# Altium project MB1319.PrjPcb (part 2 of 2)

## Sheet ST_LINK_V2-1.SchDoc: ST-LINK/V2-1
size A3; Date: Not used; ApprovedBy: Not used; CheckedBy: Not used; Author: Not used; CompanyName: STMicroelectronics; DrawnBy: Not used; Engineer: Not used; Organization: Not used; Address1: Not used; Address2: Not used; Address3: Not used; Address4: Not used; DocumentNumber: 8; Revision: Not used; SheetNumber: 8; SheetTotal: 8

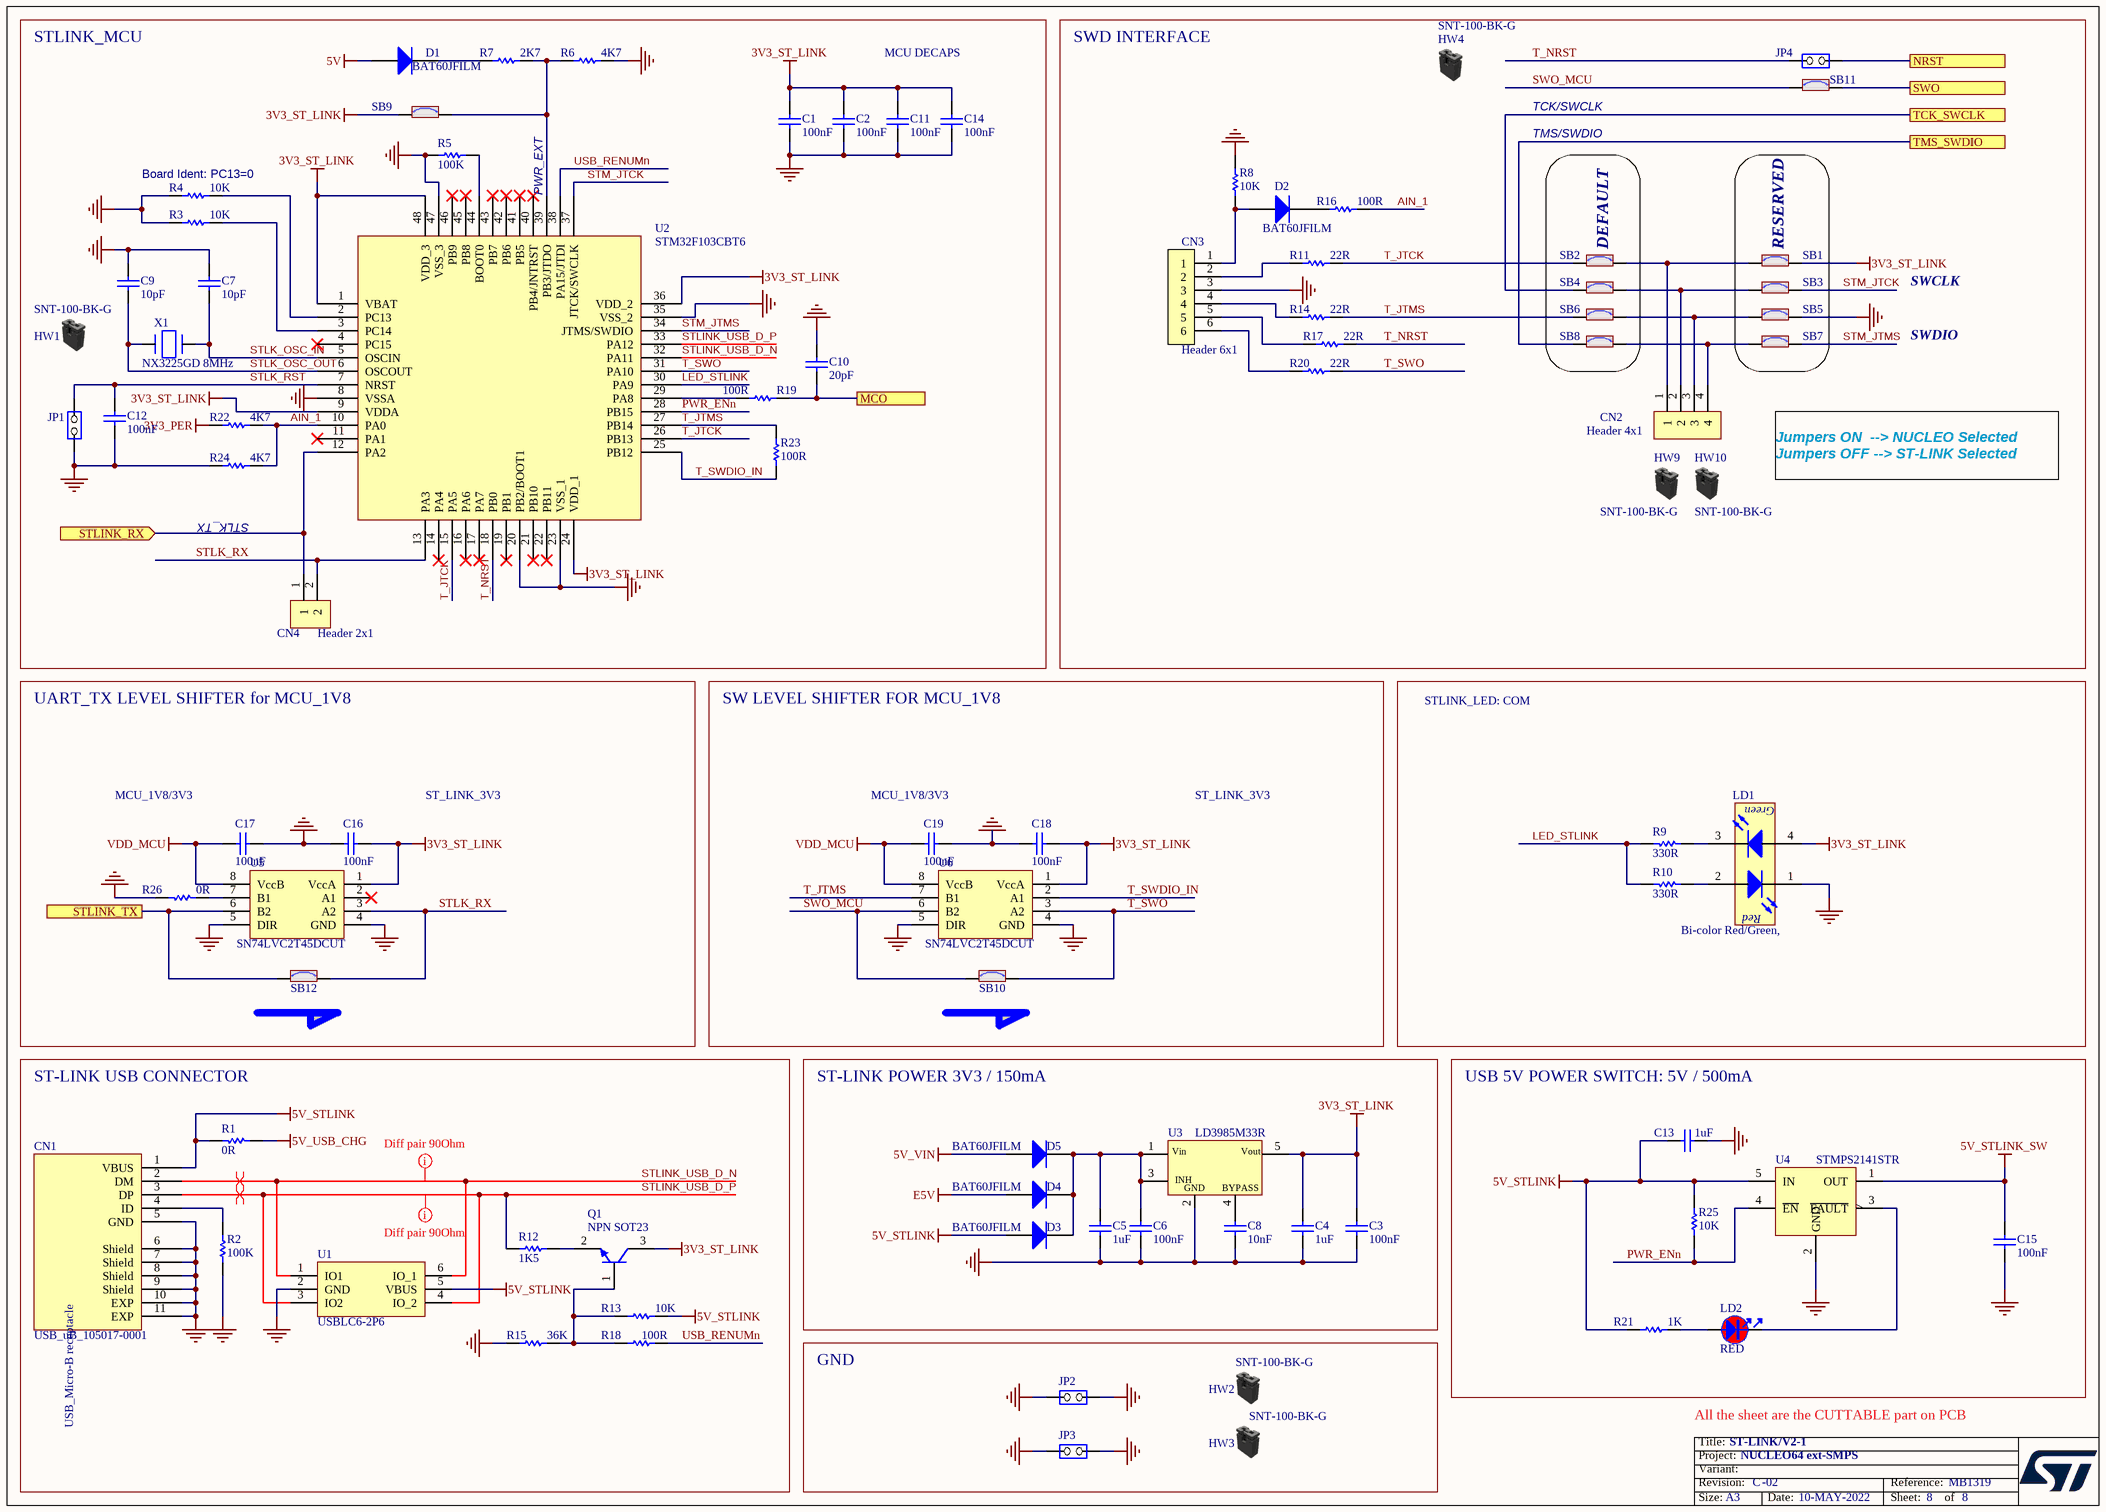
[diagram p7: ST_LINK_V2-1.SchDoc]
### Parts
C1  value 100nF  [C0603]  (hidden comment: Capacitor)
C2  value 100nF  [C0603]  (hidden comment: Capacitor)
C3  value 100nF  [C0603]  (hidden comment: Capacitor)
C4  value 1uF  [C0603]  (hidden comment: Capacitor)
C5  value 1uF  [C0603]  (hidden comment: Capacitor)
C6  value 100nF  [C0603]  (hidden comment: Capacitor)
C7  value 10pF  [C0402]  (hidden comment: Capacitor)
C8  value 10nF  [C0603]  (hidden comment: Capacitor)
C9  value 10pF  [C0402]  (hidden comment: Capacitor)
C10  value 20pF  [C0603]  (hidden comment: Capacitor)
C11  value 100nF  [C0603]  (hidden comment: Capacitor)
C12  value 100nF  [C0603]  (hidden comment: Capacitor)
C13  value 1uF  [C0603]  (hidden comment: Capacitor)
C14  value 100nF  [C0603]  (hidden comment: Capacitor)
C15  value 100nF  [C0603]  (hidden comment: Capacitor)
C16  value 100nF  [C0603]  (hidden comment: Capacitor)
C17  value 100nF  [C0603]  (hidden comment: Capacitor)
C18  value 100nF  [C0603]  (hidden comment: Capacitor)
C19  value 100nF  [C0603]  (hidden comment: Capacitor)
CN1  value USB_uB_105017-0001  [CON_USBMICROB_MOLEX_105017-0001_H2P90]  (hidden comment: USB_uB_105017.0001)
CN2  Header 4x1  [CON_SAMTEC_TSW-104-07-G-S]
CN3  Header 6x1  [CON_SAMTEC_TSW-106-07-X-S]
CN4  Header 2x1  [CON_SAMTEC_TSW-102-07-G-S]
D1  BAT60JFILM  [DIO_SOD323]
D2  BAT60JFILM  [DIO_SOD323]
D3  BAT60JFILM  [DIO_SOD323]
D4  BAT60JFILM  [DIO_SOD323]
D5  BAT60JFILM  [DIO_SOD323]
HW1  value SNT-100-BK-G  (hidden comment: Shunt Black 2.54mm)  (mechanical)
HW2  value SNT-100-BK-G  (hidden comment: Shunt Black 2.54mm)  (mechanical)
HW3  value SNT-100-BK-G  (hidden comment: Shunt Black 2.54mm)  (mechanical)
HW4  value SNT-100-BK-G  (hidden comment: Shunt Black 2.54mm)  (mechanical)
HW9  value SNT-100-BK-G  (hidden comment: Shunt Black 2.54mm)  (mechanical)
HW10  value SNT-100-BK-G  (hidden comment: Shunt Black 2.54mm)  (mechanical)
JP1  Jumper_Header 2x1  [CON_SAMTEC_TSW-102-07-G-S]  (value not drawn)
JP2  Jumper_Header 2x1  [CON_SAMTEC_TSW-102-09-X-S]  (value not drawn)
JP3  Jumper_Header 2x1  [CON_SAMTEC_TSW-102-09-X-S]  (value not drawn)
JP4  Jumper_Header 2x1  [CON_SAMTEC_TSW-102-07-G-S]  (value not drawn)
LD1  value Bi-color Red/Green,  [LED_BI-GR_HSMF-A201-A00J1]  (hidden comment: LD_BICOLOR_CMS)
LD2  value RED  [LED_0603_RED]  (hidden comment: LED_red)
Q1  value NPN SOT23  [NPN_SOT23]  (hidden comment: 9013-SOT23)
R1  value 0R  [R0603]  (hidden comment: Resistor)
R2  value 100K  [R0603]  (hidden comment: Resistor)
R3  value 10K  [R0603]  (hidden comment: Resistor)
R4  value 10K  [R0603]  (hidden comment: Resistor)
R5  value 100K  [R0603]  (hidden comment: Resistor)
R6  value 4K7  [R0603]  (hidden comment: Resistor)
R7  value 2K7  [R0603]  (hidden comment: Resistor)
R8  value 10K  [R0603]  (hidden comment: Resistor)
R9  value 330R  [R0603]  (hidden comment: Resistor)
R10  value 330R  [R0603]  (hidden comment: Resistor)
R11  value 22R  [R0603]  (hidden comment: Resistor)
R12  value 1K5  [R0603]  (hidden comment: Resistor)
R13  value 10K  [R0603]  (hidden comment: Resistor)
R14  value 22R  [R0603]  (hidden comment: Resistor)
R15  value 36K  [R0603]  (hidden comment: Resistor)
R16  value 100R  [R0603]  (hidden comment: Resistor)
R17  value 22R  [R0603]  (hidden comment: Resistor)
R18  value 100R  [R0603]  (hidden comment: Resistor)
R19  value 100R  [R0603]  (hidden comment: Resistor)
R20  value 22R  [R0603]  (hidden comment: Resistor)
R21  value 1K  [R0603]  (hidden comment: Resistor)
R22  value 4K7  [R0603]  (hidden comment: Resistor)
R23  value 100R  [R0603]  (hidden comment: Resistor)
R24  value 4K7  [R0603]  (hidden comment: Resistor)
R25  value 10K  [R0603]  (hidden comment: Resistor)
R26  value 0R  [R0603]  (hidden comment: Resistor)
SB1  SB_ON  [SOLDER-BRIDGE_R0603-0R]  (value not drawn)
SB2  SB_ON  [SOLDER-BRIDGE_R0603-0R]  (value not drawn)
SB3  SB_ON  [SOLDER-BRIDGE_R0603-0R]  (value not drawn)
SB4  SB_ON  [SOLDER-BRIDGE_R0603-0R]  (value not drawn)
SB5  SB_ON  [SOLDER-BRIDGE_R0603-0R]  (value not drawn)
SB6  SB_ON  [SOLDER-BRIDGE_R0603-0R]  (value not drawn)
SB7  SB_ON  [SOLDER-BRIDGE_R0603-0R]  (value not drawn)
SB8  SB_ON  [SOLDER-BRIDGE_R0603-0R]  (value not drawn)
SB9  SB_ON  [SOLDER-BRIDGE_R0603-0R]  (value not drawn)
SB10  SB_ON  [SOLDER-BRIDGE_R0603-0R]  (value not drawn)
SB11  SB_ON  [SOLDER-BRIDGE_R0603-0R]  (value not drawn)
SB12  SB_ON  [SOLDER-BRIDGE_R0603-0R]  (value not drawn)
U1  USBLC6-2P6  [ESD_SOT666]
U2  STM32F103CBT6  [ICC_LQFP48_7X7_P050]
U3  LD3985M33R  [REG_SOT23-5L]
U4  STMPS2141STR  [MOS_SOT23-5L]
U5  SN74LVC2T45DCUT  [ICC_VSSOP8_DCU_R-PDSO-G8_2X2P30_P050]
U6  SN74LVC2T45DCUT  [ICC_VSSOP8_DCU_R-PDSO-G8_2X2P30_P050]
X1  value NX3225GD 8MHz  [CRY_NX3225GD_2P]  (hidden comment: XTAL_2_PINS)

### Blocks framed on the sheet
STLINK_MCU: C1 C2 C7 C9-C12 C14 CN4 D1 HW1 JP1 R3-R7 R19 R22-R24 SB9 U2 X1
SWD INTERFACE: CN2 CN3 D2 HW4 HW9 HW10 JP4 R8 R11 R14 R16 R17 R20 SB11
DEFAULT: SB2 SB4 SB6 SB8
RESERVED: SB1 SB3 SB5 SB7
UART_TX LEVEL SHIFTER for MCU_1V8: C16 C17 R26 SB12 U5
SW LEVEL SHIFTER FOR MCU_1V8: C18 C19 SB10 U6
STLINK_LED: COM: LD1 R9 R10
ST-LINK USB CONNECTOR: CN1 Q1 R1 R2 R12 R13 R15 R18 U1
ST-LINK POWER 3V3 / 150mA: C3-C6 C8 D3-D5 U3
USB 5V POWER SWITCH: 5V / 500mA: C13 C15 LD2 R21 R25 U4
GND: HW2 HW3 JP2 JP3

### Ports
MCO, NRST, STLINK_RX (in), STLINK_TX, SWO, TCK_SWCLK, TMS_SWDIO

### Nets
3V3_PER: R22.1
3V3_ST_LINK: C1.2 C2.2 C3.2 C4.2 C11.2 C14.2 C16.1 C18.1 LD1.4(YellowGreen_anode) Q1.3(C) SB1.2 SB9.1 U2.1(VBAT) U2.9(VDDA) U2.24(VDD_1) U2.36(VDD_2) U2.48(VDD_3) U3.5(Vout) U5.1(VccA) U6.1(VccA)
5V: D1.1(A)
5V_STLINK: C13.1 CN1.1(VBUS) D3.1(A) R1.1 R13.1 R21.2 R25.1 U1.5(VBUS) U4.5(IN)
5V_STLINK_SW: C15.2 U4.1(OUT)
5V_USB_CHG: R1.2
5V_VIN: D5.1(A)
E5V: D4.1(A)
GND: C1.1 C2.1 C3.1 C4.1 C5.1 C6.1 C7.2 C8.1 C9.2 C10.2 C11.1 C12.1 C13.2 C14.1 C15.1 C16.2 C17.1 C18.2 C19.1 CN1.5(GND) CN1.6(Shield) CN1.7(Shield) CN1.8(Shield) CN1.9(Shield) CN1.10(EXP) CN1.11(EXP) CN3.3 JP1.1(COMMON) JP2.1(COMMON) JP2.2(NO) JP3.1(COMMON) JP3.2(NO) LD1.1(RED_cathode) R2.1 R3.1 R4.1 R5.1 R6.2 R8.2 R15.1 R24.1 R26.2 SB5.2 U1.2(GND) U2.8(VSSA) U2.20(PB2/BOOT1) U2.23(VSS_1) U2.35(VSS_2) U2.47(VSS_3) U3.2(GND) U4.2(GND) U5.4(GND) U5.5(DIR) U6.4(GND) U6.5(DIR)
VDD_MCU: C17.2 C19.2 U5.8(VccB) U6.8(VccB)
AIN_1: R16.2 R22.2 R24.2 U2.10(PA0)
LED_STLINK: R9.2 R10.2 U2.30(PA9)
MCO: C10.1 R19.2 ; port MCO
NRST: JP4.1(COMMON) ; port NRST
PA13: SB8.1 ; port TMS_SWDIO
PA14: SB4.1 ; port TCK_SWCLK
PB3: SB11.2 ; port SWO
PWR_ENn: R25.2 U2.28(PB15) U4.4(~{EN})
STLINK_RX: CN4.1 U2.12(PA2) ; port STLINK_RX
STLINK_TX: SB12.2 U5.6(B2) ; port STLINK_TX
STLINK_USB_D_N: CN1.2(DM) U1.1(IO1) U1.6(IO_1) U2.32(PA11)
STLINK_USB_D_P: CN1.3(DP) R12.2 U1.3(IO2) U1.4(IO_2) U2.33(PA12)
STLK_OSC_IN: C7.1 U2.5(OSCIN) X1.2(X2)
STLK_OSC_OUT: C9.1 U2.6(OSCOUT) X1.1(X1)
STLK_RST: C12.2 JP1.2(NO) U2.7(NRST)
STLK_RX: CN4.2 SB12.1 U2.13(PA3) U5.3(A2)
STM_JTCK: SB3.2 U2.37(JTCK/SWCLK)
STM_JTMS: SB7.2 U2.34(JTMS/SWDIO)
SWO_MCU: SB10.2 SB11.1 U6.6(B2)
T_JTCK: R11.2 SB2.1 U2.15(PA5) U2.26(PB13)
T_JTMS: R14.2 R23.2 SB6.1 U2.27(PB14) U6.7(B1)
T_NRST: JP4.2(NO) R17.2 U2.18(PB0)
T_SWDIO_IN: R23.1 U2.25(PB12) U6.2(A1)
T_SWO: R20.2 SB10.1 U2.31(PA10) U6.3(A2)
USB_RENUMn: R18.2 U2.38(PA15/JTDI)
NetC5_2: C5.2 C6.2 D3.2(K) D4.2(K) D5.2(K) U3.1(Vin) U3.3(CE)
NetC8_2: C8.2 U3.4(BYPASS)
NetCN1_4: CN1.4(ID) R2.2
NetCN2_1: CN2.1 SB1.1 SB2.2
NetCN2_2: CN2.2 SB3.1 SB4.2
NetCN2_3: CN2.3 SB5.1 SB6.2
NetCN2_4: CN2.4 SB7.1 SB8.2
NetCN3_1: CN3.1 D2.1(A) R8.1
NetCN3_2: CN3.2 R11.1
NetCN3_4: CN3.4 R14.1
NetCN3_5: CN3.5 R17.1
NetCN3_6: CN3.6 R20.1
NetD1_2: D1.2(K) R7.1
NetD2_2: D2.2(K) R16.1
NetLD1_2: LD1.2(Red_anode) R10.1
NetLD1_3: LD1.3(YellowGreen_cathode) R9.1
NetLD2_1: LD2.1 R21.1
NetLD2_2: LD2.2 U4.3(~{FAULT})
NetQ1_1: Q1.1(B) R13.2 R15.2 R18.1
NetQ1_2: Q1.2(E) R12.1
NetR3_2: R3.2 U2.3(PC14)
NetR4_2: R4.2 U2.2(PC13)
NetR5_2: R5.2 U2.44(BOOT0)
NetR6_1: R6.1 R7.2 SB9.2 U2.39(PB3/JTDO)
NetR19_1: R19.1 U2.29(PA8)
NetR26_1: R26.1 U5.7(B1)

Not connected (* = marked no-connect by the designer): U2 4(PC15)* 11(PA1)* 14(PA4)* 16(PA6)* 17(PA7)* 19(PB1)* 21(PB10)* 22(PB11)* 40(PB4/JNTRST)* 41(PB5)* 42(PB6)* 43(PB7)* 45(PB8)* 46(PB9)*; U5 2(A1)*

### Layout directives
mark named Diff pair 90Ohm: STLINK_USB_D_N, STLINK_USB_D_P
differential pair: STLINK_USB_D_N, STLINK_USB_D_P

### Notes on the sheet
- MCU DECAPS
- TCK/SWCLK
- (near R4) Board Ident: PC13=0
- TMS/SWDIO
- (near U2) PWR_EXT
- SWCLK
- SWDIO
- STLK_TX
- Jumpers ON  --> NUCLEO Selected
  Jumpers OFF --> ST-LINK Selected
- MCU_1V8/3V3
- ST_LINK_3V3
- All the sheet are the CUTTABLE part on PCB

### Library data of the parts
C1-C3 C11 C12 C14-C19 = MCD-00237: Capacitor, MLCC, 100nF, 6V3, X5R, +/-10%, 0603, T=0.8mm; Part_Preference: Not recommended; Manufacturer: YAGEO; Manufacturer_Part_Number: CC0603KRX5R5BB104; Component_Country_Of_Origin: China; ShowFields: YES; ID: 2631
C4 C13 = MCD-00238: Capacitor, MLCC, 1uF, 6V3, X5R, +/-10%, 0603, T=0,8mm; Manufacturer_Part_Number: CC0603KRX5R5BB105; Manufacturer: YAGEO; Part_Preference: Recommended
C5 = MCD-00010: Capacitor, MLCC, 1uF, 16V, X5R, +/-10%, 0603, T=0,8mm; Manufacturer_Part_Number: CC0603KRX5R7BB105; Manufacturer: YAGEO; Part_Preference: Recommended
C6 = MCD-00211: Capacitor, MLCC, 100nF, 16V, X7R, +/-10%, 0603, T=0,8mm; Manufacturer_Part_Number: CC0603KRX7R7BB104; Manufacturer: YAGEO; Part_Preference: Recommended; Order_Code_RS: 669-8763
C7 C9 = MCD-00015: Capacitor, MLCC, 10pF, 50V, NPO, +/-5%, 0402, T=0,5mm; Manufacturer_Part_Number: CC0402JRNPO9BN100; Manufacturer: YAGEO; Part_Preference: Recommended
C8 = MCD-00017: Capacitor, MLCC, 10nF, 50V, X7R, +/-10%, 0603, T=0.8mm; Manufacturer_Part_Number: CC0603KRX7R9BB103; Manufacturer: YAGEO; Part_Preference: Recommended; Order_Code_RS: 616-9537
C10 = MCD-00638: Capacitor, MLCC, 20pF, 50V, NPO, +/-5%, 0603, T=0,8mm; Manufacturer_Part_Number: CC0603JRNPO9BN200; Manufacturer: YAGEO; Part_Preference: Recommended
CN1 = MCD-00028: USB-MICRO-B, 0.65mm, RA, SMT, Bottom Mount,; Manufacturer_Part_Number: 1050170001; Manufacturer: MOLEX; Part_Type: Connector; Part_Preference: Recommended
CN2 = MCD-00029: Header, 4x1, 2,54mm, VR, TH, Height 5.84mm/2.54mm; Part_Type: Connector; Manufacturer_Part_Number: TSW-104-07-G-S; Manufacturer: SAMTEC; Part_Preference: Recommended
CN3 = MCD-00212: Header, 6x1, 2,54mm, VR, TH, Height 5.84mm/2.54mm; Manufacturer_Part_Number: TSW-106-07-G-S; Manufacturer: SAMTEC; Part_Type: Connector; Part_Preference: Recommended
CN4 = MCD-00032: Header, 2x1, 2,54mm, VR, TH, Height 5.84mm/2.54mm; Manufacturer_Part_Number: TSW-102-07-G-S; Manufacturer: SAMTEC; Part_Type: Connector; Part_Preference: Recommended; Alternate_Manufacturer: JIUBABA; Alternate_Manufacturer_Part_Number: 313102S111116
D1-D5 = MCD-00034: Manufacturer: STMICROELECTRONICS; Part_Type: Diode; BMS_Part_Number: 9151097; Part_Preference: Recommended; Manufacturer_HQ_COO: EU
HW1-HW4 HW9 HW10 = MCD-00043: SHUNT 2.54mm BLACK; Manufacturer: SAMTEC; Part_Type: Misc; Part_Preference: Recommended; Alternate_Manufacturer: JIUBABA; Alternate_Manufacturer_Part_Number: 316102S111A
JP1 JP4 = MCD-00045: Header, 2x1, 2,54mm, VR, TH, Height 5.84mm/2.54mm; Manufacturer_Part_Number: TSW-102-07-G-S; Manufacturer: SAMTEC; Part_Type: Connector; Part_Preference: Recommended; Alternate_Manufacturer: JIUBABA; LIANYI; Alternate_Manufacturer_Part_Number: 313102S111116;313102S111116; Value: Shunt not fitted
JP2 JP3 = MCD-00214: Header, 2x1, 2,54mm, VR, TH, Height 5.84mm/10.16mm; Manufacturer_Part_Number: TSW-102-09-G-S; Manufacturer: SAMTEC; Part_Type: Connector; Part_Preference: Recommended; Value: Header 2x1 16mm
LD1 = MCD-02360: Led, Bi-color Red/Green, 2V4, 30mA, 4-PLCC; Manufacturer_Part_Number: 67-22VRVGC/TR8; Manufacturer: EVERLIGHT; Part_Type: Display; Part_Preference: Recommended
LD2 = MCD-02899: LED, Red, VF : Min=1.75V , Max=2.35V, 25mA, 0603; Part_Type: Display; Part_Preference: Recommended; Manufacturer: EVERLIGHT; Manufacturer_Part_Number: 19-213/R6C-AP1Q2B/5T; Full_Alternate_Internal_Part_Number: MCD-00049; Component_Country_Of_Origin: China; ShowFields: YES; ID: 5015
Q1 = MCD-00073: NPN Bipolar Transistor; Manufacturer_Part_Number: BSR14; Manufacturer: ON SEMICONDUCTOR; Part_Type: IC; Part_Preference: Recommended; Alternate_Manufacturer_Part_Number: MMBT2222LT1G / MMBT2222ALT1G / MMBT2222ALT3G
R1 R26 = MCD-00056: Resistor,0R,0603,5%,1/10W; Manufacturer_Part_Number: RC0603JR-070RL; Manufacturer: YAGEO; Part_Preference: Recommended
R2 R5 = MCD-00223: Resistor,100K,0603,1%,1/10W; Manufacturer_Part_Number: RC0603FR-07100KL; Manufacturer: YAGEO; Part_Preference: Recommended
R3 R4 R8 R13 R25 = MCD-00220: Resistor,10K,0603,1%,1/10W; Manufacturer_Part_Number: RC0603FR-0710KL; Manufacturer: YAGEO; Part_Preference: Recommended
R6 R22 R24 = MCD-00219: Resistor,4K7,0603,1%,1/10W; Manufacturer_Part_Number: RC0603FR-074K7L; Manufacturer: YAGEO; Part_Preference: Recommended
R7 = MCD-00218: Resistor,2K7,0603,1%,1/10W; Manufacturer_Part_Number: RC0603FR-072K7L; Manufacturer: YAGEO; BMS_Part_Number: 9129767; Part_Preference: Recommended
R9 R10 = MCD-00197: Resistor,330R,0603,1%,1/10W; Manufacturer_Part_Number: RC0603FR-07330RL; Manufacturer: YAGEO; BMS_Part_Number: 9129729; Part_Preference: Recommended
R11 R14 R17 R20 = MCD-00066: Resistor,22R,0603,1%,1/10W; Manufacturer_Part_Number: RC0603FR-0722RL; Manufacturer: YAGEO; Part_Preference: Recommended
R12 = MCD-00217: Resistor,1K5,0603,1%,1/10W; Manufacturer_Part_Number: RC0603FR-071K5L; Manufacturer: YAGEO; BMS_Part_Number: 9129766; Part_Preference: Recommended
R15 = MCD-00221: Resistor,36K,0603,1%,1/10W; Manufacturer_Part_Number: RC0603FR-0736KL; Manufacturer: YAGEO; Part_Preference: Recommended
R16 R18 R19 R23 = MCD-00224: Resistor,100R,0603,1%,1/10W; Manufacturer_Part_Number: RC0603FR-07100RL; Manufacturer: YAGEO; Part_Preference: Recommended
R21 = MCD-00070: Resistor,1K,0603,1%,1/10W; Manufacturer_Part_Number: RC0603FR-071KL; Manufacturer: YAGEO; Part_Preference: Recommended
SB1-SB12 = MCD-00071: Solder Bridge ON; Part_Type: Misc; Part_Preference: Recommended; Manufacturer: YAGEO; Manufacturer_Part_Number: RC0603JR-070RL
U1 = MCD-00169: USB OTG FS ESD protection; Manufacturer: STMICROELECTRONICS; Part_Type: IC; BMS_Part_Number: 9151057; Part_Preference: Recommended; Manufacturer_HQ_COO: EU
U2 = MCD-00085: Medium-density performance line ARM-based 32-bit MCU with 128KB Flash; Manufacturer: STMICROELECTRONICS; Part_Type: IC; BMS_Part_Number: 9175111; Part_Preference: Recommended; Manufacturer_HQ_COO: EU
U3 = MCD-00086: Ultra low drop-low noise BiCMOS voltage, regulators low ESR capacitors compatible; Manufacturer: STMICROELECTRONICS; Part_Type: IC; BMS_Part_Number: 9176161; Part_Preference: Recommended; Manufacturer_HQ_COO: EU
U4 = MCD-00083: Enhanced single channel power switches with active low enable pin; Part_Type: IC; Manufacturer: STMICROELECTRONICS; Alternate_Manufacturer_Part_Number: TPS2041C; Alternate_Manufacturer: TEXAS INSTRUMENTS; BMS_Part_Number: 9159003; Part_Preference: Recommended; Manufacturer_HQ_COO: EU
U5 U6 = MCD-00264: Dual bit dual supply bus transceiver; Part_Type: IC; Manufacturer: TEXAS INSTRUMENTS; BMS_Part_Number: 9169311; Part_Preference: Recommended
X1 = MCD-00092: Crystal 8MHz, 8pF, +-20ppm, 500ohms max,  SMD; Manufacturer_Part_Number: NX3225GD 8MHz EXS00A-CG04874; Manufacturer: NDK; Part_Type: Crystal oscillator; BMS_Part_Number: 9157029; Part_Preference: Recommended

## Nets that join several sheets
3V3: Arduino_extension_connectors (CN5.16 CN8.4 SB21.2), Power (JP6.1 SB13.2 SB20.1)
3V3_PER: Arduino_extension_connectors (R34.1 SB15.2), Power (SB20.2), ST_LINK_V2-1 (R22.1)
5V: Arduino_extension_connectors (CN5.18 CN8.5), Power (9 pins), ST_LINK_V2-1 (D1.1)
5V_STLINK: Arduino_extension_connectors (CN6.8), ST_LINK_V2-1 (9 pins)
5V_STLINK_SW: Power (JP5.1), ST_LINK_V2-1 (C15.2 U4.1)
5V_USB_CHG: Power (JP5.7), ST_LINK_V2-1 (R1.2)
5V_VIN: Arduino_extension_connectors (R35.2), Power (C29.2 JP5.3 U8.2 U8.4), ST_LINK_V2-1 (D5.1)
AGND: STM32_microcontroller_power (C40.2 C41.1 SB56.2 U9.12), Arduino_extension_connectors (CN6.32)
AVDD: STM32_microcontroller_power (5 pins), Arduino_extension_connectors (CN6.7 CN7.8)
E5V: Arduino_extension_connectors (CN5.6), Power (JP5.5), ST_LINK_V2-1 (D4.1)
GND: STM32_microcontroller_IOs (12 pins), STM32_microcontroller_power (14 pins), Arduino_extension_connectors (11 pins), Power (10 pins), Power SMPS (27 pins), ST_LINK_V2-1 (55 pins)
VBAT: STM32_microcontroller_power (C39.1 SB61.1 SB65.1 U9.1), Arduino_extension_connectors (CN5.33)
VDD: STM32_microcontroller_power (SB24.1 SB65.2 SB77.1), Arduino_extension_connectors (CN5.5), Power (JP6.2), Power SMPS (CN11.1 JP7.1 JP8.1 SB76.1)
VDD_1V2: STM32_microcontroller_power (C33.2 C34.2 U9.30 U9.62), Power SMPS (SB39.2 SB43.2 SB46.2 SB51.2)
VDD_MCU: STM32_microcontroller_IOs (B1.1 B1.2), STM32_microcontroller_power (10 pins), Arduino_extension_connectors (SB14.2), Power SMPS (JP7.2 SB87.2), ST_LINK_V2-1 (C17.2 C19.2 U5.8 U6.8)
VIN: Arduino_extension_connectors (CN5.24 CN8.8), Power (C28.2 U8.3)
ARD_D0_RX: STM32_microcontroller_IOs (SB33.2 SB73.2), Arduino_extension_connectors (CN6.37 CN9.1)
ARD_D1_TX: STM32_microcontroller_IOs (SB35.2 SB60.2), Arduino_extension_connectors (CN6.35 CN9.2)
BOOT0: STM32_microcontroller_IOs (R32.2 SB45.2 SB48.2), Arduino_extension_connectors (CN5.7)
MCO: STM32_microcontroller_IOs (SB64.1), ST_LINK_V2-1 (C10.1 R19.2)
NRST: STM32_microcontroller_IOs (C23.2 R31.1 U9.7), Arduino_extension_connectors (CN5.14 CN8.3), Power SMPS (U10.8), ST_LINK_V2-1 (JP4.1)
PA0: STM32_microcontroller_IOs (SB62.2 U9.14), Arduino_extension_connectors (CN5.28 CN10.1)
PA1: STM32_microcontroller_IOs (U9.15), Arduino_extension_connectors (CN5.30 CN10.2)
PA2: STM32_microcontroller_IOs (SB60.1 SB66.2 U9.16), Arduino_extension_connectors (CN6.38)
PA3: STM32_microcontroller_IOs (SB73.1 SB75.2 U9.17), Arduino_extension_connectors (CN6.36)
PA4: STM32_microcontroller_IOs (U9.20), Arduino_extension_connectors (CN6.30), Power SMPS (SB92.2)
PA5: STM32_microcontroller_IOs (U9.21), Arduino_extension_connectors (CN6.28), Power SMPS (SB89.2)
PA6: STM32_microcontroller_IOs (U9.22), Arduino_extension_connectors (CN6.26), Power SMPS (SB93.2)
PA7: STM32_microcontroller_IOs (U9.23), Arduino_extension_connectors (CN6.24), Power SMPS (SB88.2)
PA8: STM32_microcontroller_IOs (U9.41), Arduino_extension_connectors (CN6.19 CN7.2)
PA9: STM32_microcontroller_IOs (SB34.2 SB35.1 U9.42), Arduino_extension_connectors (CN6.14)
PA10: STM32_microcontroller_IOs (SB32.2 SB33.1 U9.43), Arduino_extension_connectors (CN6.12)
PA11: STM32_microcontroller_IOs (U9.44), Arduino_extension_connectors (CN6.17 CN7.3)
PA12: STM32_microcontroller_IOs (U9.45), Arduino_extension_connectors (CN6.33 CN9.3)
PA13: STM32_microcontroller_IOs (U9.46), Arduino_extension_connectors (CN5.15), ST_LINK_V2-1 (SB8.1)
PA14: STM32_microcontroller_IOs (U9.49), Arduino_extension_connectors (CN5.17), ST_LINK_V2-1 (SB4.1)
PA15: STM32_microcontroller_IOs (U9.50), Arduino_extension_connectors (CN6.27 CN9.6)
PB0: STM32_microcontroller_IOs (SB57.2 SB63.2), Arduino_extension_connectors (CN6.10)
PB1: STM32_microcontroller_IOs (SB47.2 SB52.2), Arduino_extension_connectors (CN6.22)
PB2: STM32_microcontroller_IOs (SB40.2 SB44.2), Arduino_extension_connectors (CN6.18)
PB3: STM32_microcontroller_IOs (SB18.2 SB19.2), Arduino_extension_connectors (CN6.31 CN9.4), ST_LINK_V2-1 (SB11.2)
PB4: STM32_microcontroller_IOs (SB22.2 SB23.2), Arduino_extension_connectors (CN5.35)
PB5: STM32_microcontroller_IOs (SB26.2 SB27.2), Arduino_extension_connectors (CN6.29 CN9.5)
PB6: STM32_microcontroller_IOs (SB28.2 SB36.2), Arduino_extension_connectors (CN6.21 CN7.1)
PB7: STM32_microcontroller_IOs (SB38.2 SB41.1), Arduino_extension_connectors (CN6.5 CN7.9)
PB8: STM32_microcontroller_IOs (SB53.2 SB55.2), Arduino_extension_connectors (CN6.3 CN7.10)
PB9: STM32_microcontroller_IOs (SB58.2), Arduino_extension_connectors (CN5.37)
PB10: STM32_microcontroller_IOs (SB49.2 SB54.2), Arduino_extension_connectors (CN6.25 CN9.7)
PB11: STM32_microcontroller_IOs (SB37.2), Arduino_extension_connectors (CN6.16)
PB12: STM32_microcontroller_IOs (U9.33), Arduino_extension_connectors (CN5.13)
PB13: STM32_microcontroller_IOs (U9.34), Arduino_extension_connectors (CN6.11 CN7.6 SB17.1)
PB14: STM32_microcontroller_IOs (U9.35), Arduino_extension_connectors (CN6.13 CN7.5)
PB15: STM32_microcontroller_IOs (U9.36), Arduino_extension_connectors (CN6.15 CN7.4)
PC0: STM32_microcontroller_IOs (U9.8), Arduino_extension_connectors (CN5.38 CN10.6)
PC1: STM32_microcontroller_IOs (U9.9), Arduino_extension_connectors (CN5.36 CN10.5)
PC2: STM32_microcontroller_IOs (U9.10), Arduino_extension_connectors (CN5.34 CN10.4)
PC3: STM32_microcontroller_IOs (U9.11), Arduino_extension_connectors (CN5.32 CN10.3)
PC4: STM32_microcontroller_IOs (U9.24), Arduino_extension_connectors (CN6.34)
PC5: STM32_microcontroller_IOs (SB59.2), Arduino_extension_connectors (CN6.6)
PC6: STM32_microcontroller_IOs (U9.37), Arduino_extension_connectors (CN6.4)
PC7: STM32_microcontroller_IOs (U9.38), Arduino_extension_connectors (CN6.23 CN9.8)
PC8: STM32_microcontroller_IOs (U9.39), Arduino_extension_connectors (CN6.2)
PC9: STM32_microcontroller_IOs (U9.40), Arduino_extension_connectors (CN6.1)
PC10: STM32_microcontroller_IOs (U9.51), Arduino_extension_connectors (CN5.1)
PC11: STM32_microcontroller_IOs (U9.52), Arduino_extension_connectors (CN5.2)
PC12: STM32_microcontroller_IOs (U9.53), Arduino_extension_connectors (CN5.3)
PC13: STM32_microcontroller_IOs (SB50.2 U9.2), Arduino_extension_connectors (CN5.23)
PC14: STM32_microcontroller_IOs (SB72.1), Arduino_extension_connectors (CN5.25)
PC15: STM32_microcontroller_IOs (SB71.1), Arduino_extension_connectors (CN5.27)
PD2: STM32_microcontroller_IOs (SB16.2), Arduino_extension_connectors (CN5.4)
PH0: STM32_microcontroller_IOs (SB70.1), Arduino_extension_connectors (CN5.29)
PH1: STM32_microcontroller_IOs (SB68.1), Arduino_extension_connectors (CN5.31)
STLINK_RX: STM32_microcontroller_IOs (SB32.1 SB75.1), ST_LINK_V2-1 (CN4.1 U2.12)
STLINK_TX: STM32_microcontroller_IOs (SB34.1 SB66.1), ST_LINK_V2-1 (SB12.2 U5.6)

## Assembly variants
L433RC_P: not fitted C10 C42 C47 C48 CN11 HW1 HW11 HW104 HW105 HW106 HW107 HW108 HW109 R3 R19 R23 R40 R44 SB1 SB3 SB5 SB7 SB9 SB10 SB12 SB15 SB16 SB19 SB21 SB23 SB24 SB27 SB31 SB32 SB34 SB36 SB40 SB41 SB42 SB43 SB47 SB48 SB49 SB51 SB55 SB57 SB59 SB60 SB62 SB64 SB65 SB67 SB69 SB71 SB72 SB73 SB74 SB77 SB79 SB81 SB82 SB83 SB85 SB86 SB90 SB91 SB94 SB96 SB97 U12 U14 X2
L452RE_P: not fitted C10 C42 C47 C48 CN11 HW1 HW11 HW104 HW105 HW106 HW107 HW108 HW109 R3 R19 R23 R40 R44 SB1 SB3 SB5 SB7 SB9 SB10 SB12 SB15 SB16 SB19 SB21 SB23 SB24 SB27 SB31 SB32 SB34 SB36 SB40 SB41 SB42 SB43 SB47 SB48 SB49 SB51 SB55 SB57 SB59 SB60 SB62 SB64 SB65 SB67 SB69 SB71 SB72 SB73 SB74 SB77 SB79 SB81 SB82 SB83 SB85 SB86 SB90 SB91 SB94 SB96 SB97 U12 U14 X2; alternate parts U9 -> MCD-00296
L412RB_P: not fitted C10 C42 C47 C48 CN11 HW1 HW11 HW104 HW105 HW106 HW107 HW108 HW109 R3 R19 R23 R40 R44 SB1 SB3 SB5 SB7 SB9 SB10 SB12 SB15 SB16 SB19 SB21 SB23 SB24 SB27 SB31 SB32 SB34 SB36 SB40 SB41 SB42 SB43 SB47 SB48 SB49 SB51 SB55 SB57 SB59 SB60 SB62 SB64 SB65 SB67 SB69 SB71 SB72 SB73 SB74 SB77 SB79 SB81 SB82 SB83 SB85 SB86 SB90 SB91 SB94 SB96 SB97 U12 U14 X2; alternate parts U9 -> MCD-01365
L412RB_P_S: not fitted C10 C42 C47 C48 CN11 HW1 HW104 HW105 HW106 HW107 HW108 HW109 R3 R19 R23 R40 R44 SB1 SB3 SB5 SB7 SB9 SB10 SB12 SB15 SB16 SB19 SB21 SB23 SB24 SB27 SB31 SB32 SB34 SB36 SB40 SB41 SB42 SB43 SB47 SB48 SB49 SB51 SB55 SB57 SB59 SB60 SB62 SB64 SB65 SB67 SB69 SB71 SB72 SB73 SB74 SB77 SB79 SB81 SB82 SB83 SB85 SB86 SB90 SB91 SB94 SB96 SB97 U12 U14 X2; alternate parts U9 -> MCD-01365, C46 -> MCD-02066, C45 -> MCD-02066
